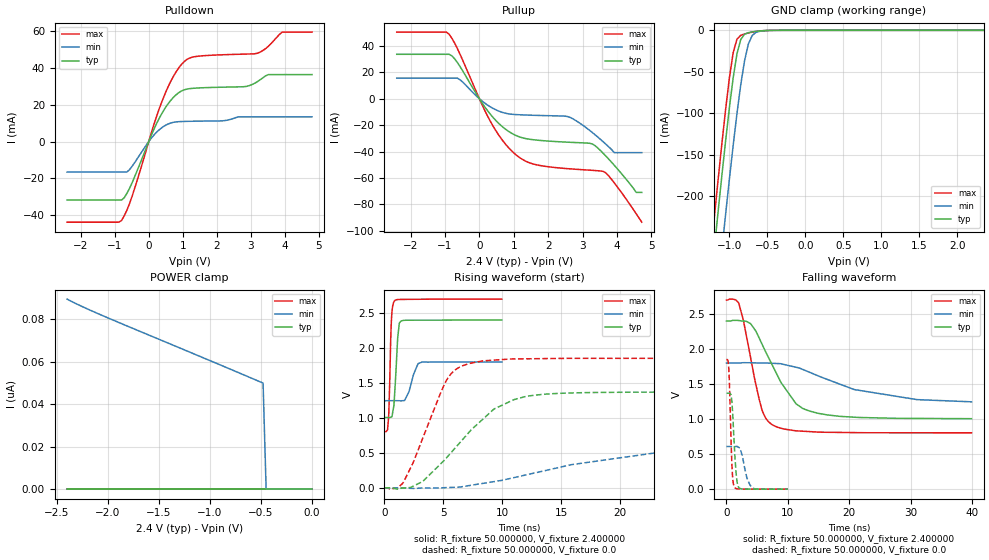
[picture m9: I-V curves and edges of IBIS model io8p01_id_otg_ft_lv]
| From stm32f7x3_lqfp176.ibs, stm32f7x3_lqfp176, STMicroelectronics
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|   Model io8p01_id_otg_ft_lv
[Model]  io8p01_id_otg_ft_lv
Model_type I/O
Polarity   Non-Inverting
Enable   Active-Low
Vinl =   0.720000V
Vinh =   1.680000V
Vmeas =  1.200000V
Cref =   50.000000pF
Rref =   100.000000M
Vref =   0.0V
C_comp   2.229800pF   2.169700pF   2.325100pF
[Temperature Range]   25.000000   0.125000k   -40.000000
[Pullup Reference]   2.400000V   1.800000V   2.700000V
[Pulldown Reference]   0.0V   0.0V   0.0V
[POWER Clamp Reference]   2.400000V   1.800000V   2.700000V
[GND Clamp Reference]   0.0V   0.0V   0.0V
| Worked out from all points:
|   slope of the pulldown table from 0 to 0.36 V, typ, clamps not added: 25 ohm
|   slope of the pullup table from 0 to 0.36 V, typ, clamps not added: 27.7 ohm
|   GND clamp passes 1 mA (typ) near -0.62 V on its own axis
|   rising waveform, R_fixture 50.000000, V_fixture 2.400000: 20-80 % time 273ps typ, 608ps min, 183ps max; typ from 1.01 V to 2.4 V
|   rising waveform, R_fixture 50.000000, V_fixture 0.0: 20-80 % time 4.75ns typ, 12.1ns min, 2.64ns max; typ from 0 V to 1.37 V
|   falling waveform, R_fixture 50.000000, V_fixture 2.400000: 20-80 % time 5.28ns typ, 12.4ns min, 2.67ns max; typ from 2.4 V to 1.01 V
|   falling waveform, R_fixture 50.000000, V_fixture 0.0: 20-80 % time 525ps typ, 978ps min, 384ps max; typ from 1.37 V to 0 V
[Pulldown]
|Voltage   I(typ)   I(min)   I(max)
-2.4V     -31.73mA   -16.51mA   -43.74mA
-800mV    -31.73mA   -16.51mA   -42.87mA
-480mV    -21.98mA   -13.17mA   -29.21mA
80mV      3.63mA     1.966mA    5.014mA
480mV     18.16mA    8.738mA    26.02mA
800mV     25.38mA    10.72mA    37.77mA
1.12V     28.53mA    11.02mA    44.6mA
2.8V      29.84mA    13.49mA    47.53mA
3.2V      32.65mA    13.49mA    48.05mA
3.52V     36.43mA    13.49mA    51.84mA
3.92V     36.43mA    13.49mA    59.49mA
4.8V      36.43mA    13.49mA    59.49mA
[Pullup]
|Voltage   I(typ)   I(min)   I(max)
-2.4V     33.57mA    15.56mA    50.37mA
-960mV    33.57mA    15.56mA    50.37mA
-560mV    24.29mA    14.3mA     33.55mA
320mV     -11.75mA   -6.207mA   -17.08mA
960mV     -26.47mA   -11.82mA   -40.02mA
1.52V     -30.88mA   -12.51mA   -49.05mA
2.56V     -32.88mA   -13.48mA   -52.9mA
3.28V     -34.19mA   -25.52mA   -54.18mA
3.6V      -41.31mA   -32.62mA   -54.97mA
3.92V     -50.32mA   -40.8mA    -63.63mA
4.56V     -70.9mA    -40.8mA    -87.08mA
4.72V     -70.9mA    -40.8mA    -93.4mA
[GND_clamp]
|Voltage   I(typ)   I(min)   I(max)
-2.4V     -1.424A    -1.508A    -1.393A
-1.25V    -311.2mA   -401.9mA   -273.3mA
-1.2V     -265.4mA   -356.1mA   -227.2mA
-1.15V    -220.4mA   -310.8mA   -181.9mA
-1.1V     -176.3mA   -266.2mA   -137.9mA
-1.05V    -133.8mA   -222.5mA   -95.88mA
-950mV    -57.31mA   -138.9mA   -26.99mA
-900mV    -28.28mA   -100.4mA   -10.61mA
-850mV    -11.02mA   -65.55mA   -5.978mA
-750mV    -2.847mA   -16.51mA   -3.192mA
-600mV    -755.4uA   -1.17mA    -743.6uA
2.35V     0A         0A         0A
[POWER_clamp]
|Voltage   I(typ)   I(min)   I(max)
-2.4V     0A         89.62nA    0A
-2.04V    0A         81.58nA    0A
-480mV    0A         50.01nA    0A
-450mV    0A         0A         0A
0V        0A         0A         0A
[Ramp]
| variable   typ   min   max
dV/dt_r  0.82218/4.74154n   0.38456/12.99182n   1.11108/2.63393n
dV/dt_f  0.83670/5.27520n   0.32352/13.32667n   1.13759/2.66685n
R_load = 50.000000
[Rising Waveform]
R_fixture= 50.000000
V_fixture= 2.400000
V_fixture_min= 1.800000
V_fixture_max= 2.700000
|time   V(typ)   V(min)   V(max)
0s        1.006V     1.247V     804.6mV
260.3ps   1.006V     1.247V     831mV
340.3ps   1.006V     1.247V     988.2mV
600.6ps   1.014V     1.247V     2.436V
860.9ps   1.34V      1.247V     2.675V
1.121ns   2.14V      1.247V     2.692V
1.381ns   2.382V     1.245V     2.694V
1.722ns   2.396V     1.255V     2.695V
3.183ns   2.398V     1.798V     2.697V
9.97ns    2.4V       1.8V       2.7V
[Rising Waveform]
R_fixture= 50.000000
V_fixture= 0.0
V_fixture_min= 0.0
V_fixture_max= 0.0
|time   V(typ)   V(min)   V(max)
0s        177.8uV    73.73uV    445uV
1.602ns   -2.723mV   -101.4uV   77.63mV
3.283ns   97.06mV    -710.2uV   724.6mV
5.205ns   417.9mV    3.855mV    1.52V
6.006ns   570.5mV    9.468mV    1.686V
7.127ns   784.3mV    31.44mV    1.775V
9.369ns   1.133V     91.56mV    1.828V
12.97ns   1.329V     221.7mV    1.847V
24.82ns   1.369V     543.2mV    1.852V
39.88ns   1.37V      609mV      1.852V
[Falling Waveform]
R_fixture= 50.000000
V_fixture= 2.400000
V_fixture_min= 1.800000
V_fixture_max= 2.700000
|time   V(typ)   V(min)   V(max)
0s        2.4V       1.8V       2.7V
2.002ns   2.407V     1.801V     2.655V
2.723ns   2.4V       1.805V     2.423V
3.924ns   2.363V     1.805V     1.881V
5.766ns   2.075V     1.8V       1.137V
7.608ns   1.745V     1.796V     912.4mV
11.37ns   1.216V     1.739V     832.7mV
14.81ns   1.085V     1.622V     815.3mV
20.82ns   1.027V     1.422V     807.5mV
39.88ns   1.006V     1.247V     804.6mV
[Falling Waveform]
R_fixture= 50.000000
V_fixture= 0.0
V_fixture_min= 0.0
V_fixture_max= 0.0
|time   V(typ)   V(min)   V(max)
0s        1.37V      609mV      1.852V
380.4ps   1.37V      609.1mV    1.72V
480.5ps   1.37V      609mV      1.523V
880.9ps   1.257V     608.8mV    366mV
1.061ns   1.004V     608.6mV    117.8mV
1.281ns   623.1mV    608.4mV    33.14mV
1.702ns   120.4mV    610.5mV    6.105mV
2.102ns   16.2mV     591.5mV    3.034mV
3.864ns   1.015mV    53.33mV    1.346mV
9.97ns    177.8uV    73.73uV    445uV
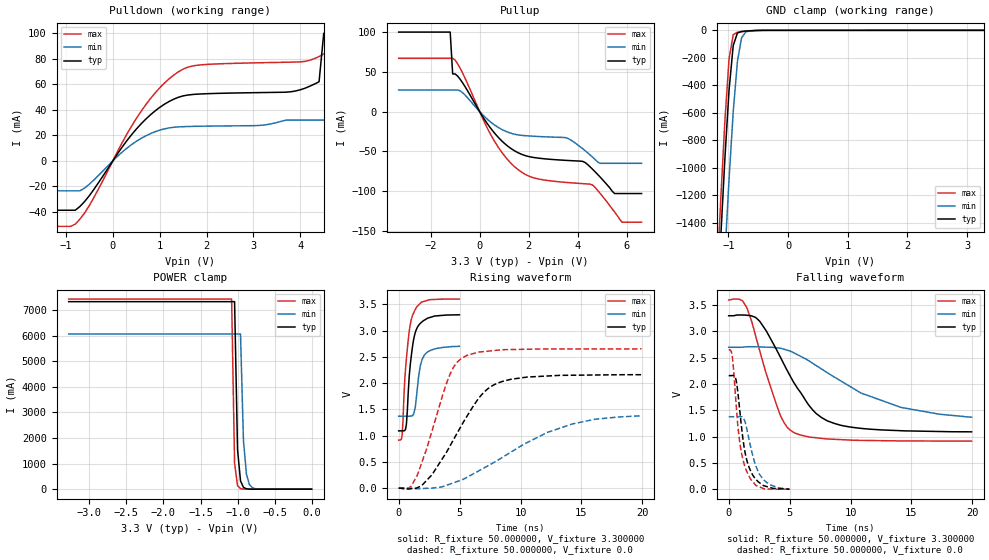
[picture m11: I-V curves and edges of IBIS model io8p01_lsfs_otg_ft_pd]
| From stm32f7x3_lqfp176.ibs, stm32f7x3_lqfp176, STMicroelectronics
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|   Model io8p01_lsfs_otg_ft_pd
[Model]  io8p01_lsfs_otg_ft_pd
Model_type I/O
Polarity   Non-Inverting
Enable   Active-Low
Vinl =   0.990000V
Vinh =   2.310000V
Vmeas =  1.650000V
Cref =   50.000000pF
Rref =   100.000000M
Vref =   0.0V
C_comp   8.196500pF   7.968500pF   8.492600pF
[Temperature Range]   25.000000   0.125000k   -40.000000
[Pullup Reference]   3.300000V   2.700000V   3.600000V
[Pulldown Reference]   0.0V   0.0V   0.0V
[POWER Clamp Reference]   3.300000V   2.700000V   3.600000V
[GND Clamp Reference]   0.0V   0.0V   0.0V
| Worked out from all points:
|   slope of the pulldown table from 0 to 0.495 V, typ, clamps not added: 20.1 ohm
|   slope of the pullup table from 0 to 0.495 V, typ, clamps not added: 21.8 ohm
|   GND clamp passes 1 mA (typ) near -0.52 V on its own axis
|   POWER clamp passes 1 mA (typ) near -0.81 V on its own axis
|   rising waveform, R_fixture 50.000000, V_fixture 3.300000: 20-80 % time 528ps typ, 494ps min, 532ps max; typ from 1.09 V to 3.3 V
|   rising waveform, R_fixture 50.000000, V_fixture 0.0: 20-80 % time 3.4ns typ, 6.58ns min, 2.17ns max; typ from 0 V to 2.16 V
|   falling waveform, R_fixture 50.000000, V_fixture 3.300000: 20-80 % time 3.36ns typ, 6.55ns min, 2.12ns max; typ from 3.3 V to 1.09 V
|   falling waveform, R_fixture 50.000000, V_fixture 0.0: 20-80 % time 844ps typ, 1.02ns min, 755ps max; typ from 2.16 V to 0 V
[Pulldown]
|Voltage   I(typ)   I(min)   I(max)
-3.3V     -38.65mA   -23.43mA   -51.3mA
-800mV    -38.65mA   -23.43mA   -49.55mA
600mV     28.88mA    17.56mA    38.65mA
1.4V      49.88mA    26.66mA    69.84mA
4.1V      56.96mA    32mA       77.99mA
4.4V      62mA       32mA       81.8mA
4.5V      100mA      32mA       83.9mA
4.7V      100mA      32mA       89mA
4.8V      100mA      32mA       100mA
5.1V      100mA      32mA       100mA
5.2V      1A         1A         100mA
6.6V      1A         1A         1A
[Pullup]
|Voltage   I(typ)   I(min)   I(max)
-3.3V     100mA      27.2mA     67mA
-1.2V     100mA      27.2mA     67mA
-1.1V     47.4mA     27.2mA     67mA
-700mV    36.46mA    23.92mA    48.81mA
500mV     -22.94mA   -14.36mA   -31.63mA
1.3V      -46.85mA   -27.39mA   -65.63mA
2.1V      -57.1mA    -30.77mA   -82.2mA
3.5V      -61.24mA   -32.71mA   -88.93mA
4.6V      -72.4mA    -57.1mA    -92.27mA
5.5V      -103mA     -65mA      -126.2mA
5.8V      -103mA     -65mA      -139mA
6.6V      -103mA     -65mA      -139mA
[GND_clamp]
|Voltage   I(typ)   I(min)   I(max)
-3.3V     -9.479A    -9.465A    -9.974A
-1.2V     -2.125A    -2.854A    -1.857A
-1.13V    -1.511A    -2.236A    -1.236A
-1.06V    -933.3mA   -1.641A    -660.9mA
-990mV    -433.3mA   -1.082A    -207mA
-920mV    -110.3mA   -591mA     -31.46mA
-850mV    -19.8mA    -226.8mA   -13.66mA
-780mV    -8.323mA   -53.94mA   -9.521mA
-710mV    -5.297mA   -11.95mA   -6.277mA
-640mV    -3.244mA   -4.292mA   -3.591mA
3.28V     81.28uA    57.87uA    93.98uA
[POWER_clamp]
|Voltage   I(typ)   I(min)   I(max)
-3.28V    7.328A     6.064A     7.43A
-1.08V    7.328A     6.064A     7.43A
-1.04V    7.328A     6.064A     1.015A
-1V       1.545A     6.064A     138.6mA
-960mV    325.6mA    6.064A     18.93mA
-920mV    68.64mA    1.89A      2.585mA
-880mV    14.47mA    589mA      353uA
-840mV    3.05mA     183.6mA    105.2uA
-800mV    642.9uA    57.21mA    105.2uA
-720mV    28.59uA    5.557mA    105.2uA
0V        0A         0A         0A
[Ramp]
| variable   typ   min   max
dV/dt_r  1.29581/3.39732n   0.80748/6.55281n   1.59031/2.17144n
dV/dt_f  1.32150/3.36048n   0.74922/6.49511n   1.61104/2.12255n
R_load = 50.000000
[Rising Waveform]
R_fixture= 50.000000
V_fixture= 3.300000
V_fixture_min= 2.700000
V_fixture_max= 3.600000
|time   V(typ)   V(min)   V(max)
0s        1.09V      1.369V     913.9mV
290.3ps   1.09V      1.37V      1.024V
500.5ps   1.099V     1.37V      2.066V
630.6ps   1.211V     1.369V     2.456V
870.9ps   2.144V     1.369V     2.992V
1.201ns   2.794V     1.402V     3.322V
1.361ns   2.96V      1.535V     3.399V
1.782ns   3.137V     2.336V     3.52V
2.072ns   3.193V     2.519V     3.554V
4.985ns   3.299V     2.699V     3.599V
[Rising Waveform]
R_fixture= 50.000000
V_fixture= 0.0
V_fixture_min= 0.0
V_fixture_max= 0.0
|time   V(typ)   V(min)   V(max)
0s        34.48uV    22.66uV    108.4uV
800.8ps   -16.48mV   73.77uV    -1.252mV
1.522ns   8.565mV    -12.54mV   241.4mV
2.723ns   252.5mV    388.5uV    1.079V
4.204ns   799.6mV    77.67mV    2.16V
5.526ns   1.339V     196.4mV    2.518V
7.287ns   1.886V     420.8mV    2.606V
9.169ns   2.069V     679.5mV    2.637V
14.25ns   2.149V     1.223V     2.65V
19.94ns   2.159V     1.378V     2.651V
[Falling Waveform]
R_fixture= 50.000000
V_fixture= 3.300000
V_fixture_min= 2.700000
V_fixture_max= 3.600000
|time   V(typ)   V(min)   V(max)
0s        3.299V     2.699V     3.599V
880.9ps   3.313V     2.699V     3.612V
1.481ns   3.308V     2.709V     3.456V
2.563ns   3.189V     2.706V     2.621V
4.204ns   2.528V     2.682V     1.427V
5.285ns   2.051V     2.6V       1.087V
7.167ns   1.443V     2.353V     977.7mV
9.169ns   1.217V     2.064V     942.8mV
14.13ns   1.112V     1.556V     917.4mV
19.94ns   1.09V      1.369V     913.9mV
[Falling Waveform]
R_fixture= 50.000000
V_fixture= 0.0
V_fixture_min= 0.0
V_fixture_max= 0.0
|time   V(typ)   V(min)   V(max)
0s        2.159V     1.378V     2.651V
280.3ps   2.161V     1.378V     2.549V
610.6ps   2.073V     1.378V     1.617V
760.8ps   1.824V     1.379V     1.184V
981ps     1.341V     1.38V      781mV
1.451ns   583.9mV    1.185V     355.9mV
1.892ns   303.4mV    713.4mV    166.1mV
2.472ns   131.6mV    302.1mV    47.97mV
3.363ns   33.96mV    85.91mV    3.091mV
4.985ns   34.48uV    22.66uV    108.4uV
